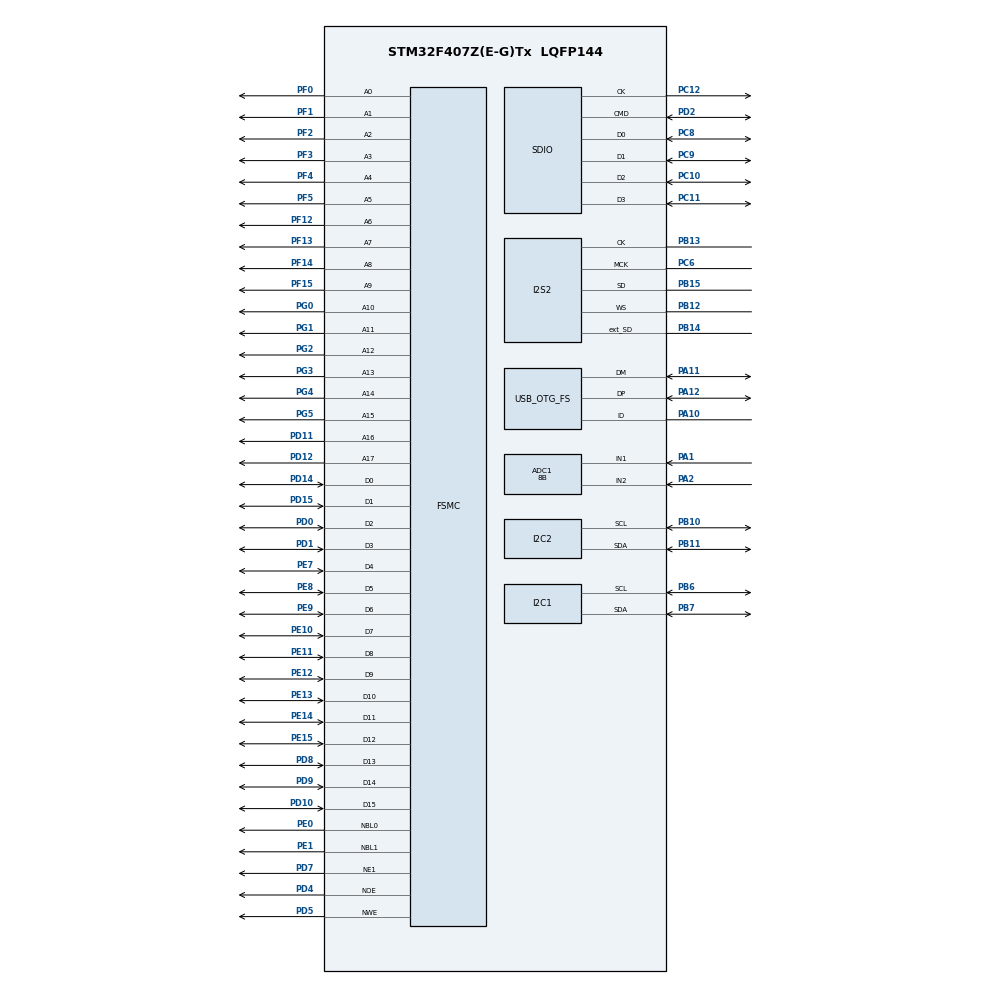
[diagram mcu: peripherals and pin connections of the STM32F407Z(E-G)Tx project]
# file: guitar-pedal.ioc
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ADC1.AutoInjectedConv=DISABLE
ADC1.Channel-0\#ChannelRegularConversion=ADC_CHANNEL_1
ADC1.ClockPrescaler=ADC_CLOCK_SYNC_PCLK_DIV2
ADC1.ContinuousConvMode=DISABLE
ADC1.DMAContinuousRequests=DISABLE
ADC1.DataAlign=ADC_DATAALIGN_RIGHT
ADC1.DiscontinuousConvMode=DISABLE
ADC1.EOCSelection=ADC_EOC_SINGLE_CONV
ADC1.EnableAnalogWatchDog=false
ADC1.ExternalTrigConv=ADC_SOFTWARE_START
ADC1.ExternalTrigConvEdge=ADC_EXTERNALTRIGCONVEDGE_NONE
ADC1.InjNumberOfConversion=0
ADC1.InjectedDiscontinuousConvMode=DISABLE
ADC1.NbrOfConversion=1
ADC1.NbrOfConversionFlag=1
ADC1.Rank-0\#ChannelRegularConversion=1
ADC1.Resolution=ADC_RESOLUTION_8B
ADC1.SamplingTime-0\#ChannelRegularConversion=ADC_SAMPLETIME_3CYCLES
ADC1.ScanConvMode=DISABLE
ADC1.master=1
Dma.I2S2_EXT_RX.1.Direction=DMA_PERIPH_TO_MEMORY
Dma.I2S2_EXT_RX.1.FIFOMode=DMA_FIFOMODE_DISABLE
Dma.I2S2_EXT_RX.1.Instance=DMA1_Stream3
Dma.I2S2_EXT_RX.1.MemDataAlignment=DMA_MDATAALIGN_BYTE
Dma.I2S2_EXT_RX.1.MemInc=DMA_MINC_ENABLE
Dma.I2S2_EXT_RX.1.Mode=DMA_NORMAL
Dma.I2S2_EXT_RX.1.PeriphDataAlignment=DMA_PDATAALIGN_BYTE
Dma.I2S2_EXT_RX.1.PeriphInc=DMA_PINC_DISABLE
Dma.I2S2_EXT_RX.1.Priority=DMA_PRIORITY_LOW
Dma.Request0=SPI2_TX
Dma.Request1=I2S2_EXT_RX
Dma.SPI2_TX.0.Direction=DMA_MEMORY_TO_PERIPH
Dma.SPI2_TX.0.FIFOMode=DMA_FIFOMODE_DISABLE
Dma.SPI2_TX.0.Instance=DMA1_Stream4
Dma.SPI2_TX.0.MemDataAlignment=DMA_MDATAALIGN_BYTE
Dma.SPI2_TX.0.MemInc=DMA_MINC_ENABLE
Dma.SPI2_TX.0.Mode=DMA_NORMAL
Dma.SPI2_TX.0.PeriphDataAlignment=DMA_PDATAALIGN_BYTE
Dma.SPI2_TX.0.PeriphInc=DMA_PINC_DISABLE
Dma.SPI2_TX.0.Priority=DMA_PRIORITY_LOW
FATFS._USE_BUFF_WO_ALIGNMENT=2
FATFS._USE_ERASE=0
FREERTOS.Tasks01=defaultTask,0,128,StartDefaultTask,Default,NULL
FREERTOS.configUSE_ALTERNATIVE_API=0
FSMC.AccessMode1=FSMC_ACCESS_MODE_A
FSMC.AsynchronousWait1=FSMC_ASYNCHRONOUS_WAIT_DISABLE
FSMC.BurstAccessMode1=FSMC_BURST_ACCESS_MODE_DISABLE
FSMC.CLKDivision1=16
FSMC.DataAddressMux1=FSMC_DATA_ADDRESS_MUX_DISABLE
FSMC.DataLatency1=17
FSMC.Extended=FSMC_NORSRAM_EXTENDED_DEVICE
FSMC.NORSRAM_Instance=FSMC_NORSRAM_DEVICE
FSMC.NSCoherentPinout1=MEMORY_PINOUT_OK
FSMC.NSMemoryDataWidth1=FSMC_NORSRAM_MEM_BUS_WIDTH_16
FSMC.PageSize1=FSMC_PAGE_SIZE_NONE
FSMC.WaitSignal1=FSMC_WAIT_SIGNAL_DISABLE
FSMC.WaitSignalActive1=FSMC_WAIT_TIMING_BEFORE_WS
FSMC.WaitSignalPolarity1=FSMC_WAIT_SIGNAL_POLARITY_LOW
FSMC.WrapMode1=FSMC_WRAP_MODE_DISABLE
FSMC.WriteBurst1=FSMC_WRITE_BURST_DISABLE
I2C1.DutyCycle=I2C_DUTYCYCLE_2
I2C1.I2C_Mode=I2C_Standard
I2C2.DutyCycle=I2C_DUTYCYCLE_2
I2C2.I2C_Mode=I2C_Fast
I2S2.AudioFreq=I2S_AUDIOFREQ_48K
I2S2.DataFormat=I2S_DATAFORMAT_24B
I2S2.ErrorAudioFreq=-0.17 %
I2S2.FullDuplexMode=I2S_FULLDUPLEXMODE_ENABLE
I2S2.Instance=SPI$Index
I2S2.MCLKOutput=I2S_MCLKOUTPUT_ENABLE
I2S2.Mode=I2S_MODE_MASTER_TX
I2S2.RealAudioFreq=47.916 KHz
I2S2.Standard=I2S_STANDARD_PHILIPS
I2S2.VirtualMode=I2S_MODE_MASTER
Mcu.Family=STM32F4
Mcu.Name=STM32F407Z(E-G)Tx
Mcu.Package=LQFP144
NVIC.DMA1_Stream3_IRQn=true\:5\:0\:false\:false\:true\:true
NVIC.DMA1_Stream4_IRQn=true\:5\:0\:false\:false\:true\:true
NVIC.PriorityGroup=NVIC_PRIORITYGROUP_4
NVIC.TIM1_UP_TIM10_IRQn=true\:0\:0\:false\:false\:true\:false
NVIC.TimeBase=TIM1_UP_TIM10_IRQn
NVIC.TimeBaseIP=TIM1
PA1.Signal=ADCx_IN1
PA10.Mode=OTG/Dual_Role_Device
PA10.Signal=USB_OTG_FS_ID
PA11.Mode=OTG/Dual_Role_Device
PA11.Signal=USB_OTG_FS_DM
PA12.Mode=OTG/Dual_Role_Device
PA12.Signal=USB_OTG_FS_DP
PA2.Signal=ADCx_IN2
PB10.GPIO_PuPdOD=GPIO_NOPULL
PB10.Mode=I2C
PB10.Signal=I2C2_SCL
PB11.GPIO_PuPdOD=GPIO_NOPULL
PB11.Mode=I2C
PB11.Signal=I2C2_SDA
PB12.Mode=Full_Duplex_Master
PB12.Signal=I2S2_WS
PB13.Mode=Full_Duplex_Master
PB13.Signal=I2S2_CK
PB14.Mode=Full_Duplex_Master
PB14.Signal=I2S2_ext_SD
PB15.Mode=Full_Duplex_Master
PB15.Signal=I2S2_SD
PB6.Mode=I2C
PB6.Signal=I2C1_SCL
PB7.Mode=I2C
PB7.Signal=I2C1_SDA
PC10.Mode=SD_4_bits_Wide_bus
PC10.Signal=SDIO_D2
PC11.Mode=SD_4_bits_Wide_bus
PC11.Signal=SDIO_D3
PC12.Mode=SD_4_bits_Wide_bus
PC12.Signal=SDIO_CK
PC6.Mode=Master_Clock_Activated
PC6.Signal=I2S2_MCK
PC8.Mode=SD_4_bits_Wide_bus
PC8.Signal=SDIO_D0
PC9.Mode=SD_4_bits_Wide_bus
PC9.Signal=SDIO_D1
PD0.Signal=FSMC_D2_DA2
PD1.Signal=FSMC_D3_DA3
PD10.Signal=FSMC_D15_DA15
PD11.Signal=FSMC_A16_CLE
PD12.Signal=FSMC_A17_ALE
PD14.Signal=FSMC_D0_DA0
PD15.Signal=FSMC_D1_DA1
PD2.Mode=SD_4_bits_Wide_bus
PD2.Signal=SDIO_CMD
PD4.Signal=FSMC_NOE
PD5.Signal=FSMC_NWE
PD7.Mode=NorPsramChipSelect1_1
PD7.Signal=FSMC_NE1
PD8.Signal=FSMC_D13_DA13
PD9.Signal=FSMC_D14_DA14
PE0.Signal=FSMC_NBL0
PE1.Signal=FSMC_NBL1
PE10.Signal=FSMC_D7_DA7
PE11.Signal=FSMC_D8_DA8
PE12.Signal=FSMC_D9_DA9
PE13.Signal=FSMC_D10_DA10
PE14.Signal=FSMC_D11_DA11
PE15.Signal=FSMC_D12_DA12
PE7.Signal=FSMC_D4_DA4
PE8.Signal=FSMC_D5_DA5
PE9.Signal=FSMC_D6_DA6
PF0.Signal=FSMC_A0
PF1.Signal=FSMC_A1
PF12.Signal=FSMC_A6
PF13.Signal=FSMC_A7
PF14.Signal=FSMC_A8
PF15.Signal=FSMC_A9
PF2.Signal=FSMC_A2
PF3.Signal=FSMC_A3
PF4.Signal=FSMC_A4
PF5.Signal=FSMC_A5
PG0.Signal=FSMC_A10
PG1.Signal=FSMC_A11
PG2.Signal=FSMC_A12
PG3.Signal=FSMC_A13
PG4.Signal=FSMC_A14
PG5.Signal=FSMC_A15
PH0-OSC_IN.Mode=HSE-External-Oscillator
PH0-OSC_IN.Signal=RCC_OSC_IN
PH1-OSC_OUT.Mode=HSE-External-Oscillator
PH1-OSC_OUT.Signal=RCC_OSC_OUT
ProjectManager.HeapSize=0x200
ProjectManager.StackSize=0x400
ProjectManager.TargetToolchain=SW4STM32
RCC.48MHZClocksFreq_Value=48000000
RCC.AHBFreq_Value=16000000
RCC.APB1Freq_Value=16000000
RCC.APB1TimFreq_Value=16000000
RCC.APB2Freq_Value=16000000
RCC.APB2TimFreq_Value=16000000
RCC.ClockTypeHCLK=RCC_CLOCKTYPE_HCLK
RCC.ClockTypePCLK1=RCC_CLOCKTYPE_PCLK1
RCC.ClockTypePCLK2=RCC_CLOCKTYPE_PCLK2
RCC.ClockTypeSysClk=RCC_CLOCKTYPE_SYSCLK
RCC.CortexFreq_Value=16000000
RCC.EnableExtClockForI2S=false
RCC.EnableHSE=true
RCC.EnableHSERTCDevisor=false
RCC.EnableLSE=false
RCC.EnableLSERTC=false
RCC.ExtClockEnable=false
RCC.HCLKFreq_Value=16000000
RCC.HSEState=RCC_HSE_ON
RCC.HSE_VALUE=16000000
RCC.HSIState=RCC_HSI_ON
RCC.HSI_VALUE=16000000
RCC.I2SEnable=true
RCC.IWDGEnable=false
RCC.LSE_VALUE=32768
RCC.LSIState=RCC_LSI_OFF
RCC.MCO1OutPutEnable=false
RCC.MCO2OutPutEnable=false
RCC.OscillatorTypeHSE=RCC_OSCILLATORTYPE_HSE
RCC.OscillatorTypeHSI=RCC_OSCILLATORTYPE_HSI
RCC.PLLI2SN=184
RCC.PLLI2SR=3
RCC.PLLSource=RCC_PLLSOURCE_HSE
RCC.PLLSourceVirtual=RCC_PLLSOURCE_HSE
RCC.PLLState=RCC_PLL_ON
RCC.RCC_PERIPHCLK_I2SVar=RCC_PERIPHCLK_I2S
RCC.RCC_PERIPHCLK_RTCVar=RCC_PERIPHCLK_RTC
RCC.RNGEnable=false
RCC.RTCEnable=false
RCC.SDIOEnable=true
RCC.SYSCLKFreq_VALUE=16000000
RCC.SYSCLKSource=RCC_SYSCLKSOURCE_HSI
RCC.USBFSEnable=true
RCC.USBHSEnable=false
RCC.VCOOutputFreq_Value=192000000
RCC.VDD_VALUE=3.3
SDIO.BusWide=SDIO_BUS_WIDE_1B
SDIO.ClockBypass=SDIO_CLOCK_BYPASS_DISABLE
SDIO.ClockEdge=SDIO_CLOCK_EDGE_RISING
SDIO.ClockPowerSave=SDIO_CLOCK_POWER_SAVE_DISABLE
SDIO.HardwareFlowControl=SDIO_HARDWARE_FLOW_CONTROL_DISABLE
SDIO.WideMode=SDIO_BUS_WIDE_4B
SH.ADCx_IN1.0=ADC1_IN1,IN1
SH.ADCx_IN2.0=ADC1_IN2,IN2
SH.FSMC_A0.0=FSMC_A0,18b-a1
SH.FSMC_A1.0=FSMC_A1,18b-a1
SH.FSMC_A10.0=FSMC_A10,18b-a1
SH.FSMC_A11.0=FSMC_A11,18b-a1
SH.FSMC_A12.0=FSMC_A12,18b-a1
SH.FSMC_A13.0=FSMC_A13,18b-a1
SH.FSMC_A14.0=FSMC_A14,18b-a1
SH.FSMC_A15.0=FSMC_A15,18b-a1
SH.FSMC_A16_CLE.0=FSMC_A16,18b-a1
SH.FSMC_A17_ALE.0=FSMC_A17,18b-a1
SH.FSMC_A2.0=FSMC_A2,18b-a1
SH.FSMC_A3.0=FSMC_A3,18b-a1
SH.FSMC_A4.0=FSMC_A4,18b-a1
SH.FSMC_A5.0=FSMC_A5,18b-a1
SH.FSMC_A6.0=FSMC_A6,18b-a1
SH.FSMC_A7.0=FSMC_A7,18b-a1
SH.FSMC_A8.0=FSMC_A8,18b-a1
SH.FSMC_A9.0=FSMC_A9,18b-a1
SH.FSMC_D0_DA0.0=FSMC_D0,16b-d1
SH.FSMC_D10_DA10.0=FSMC_D10,16b-d1
SH.FSMC_D11_DA11.0=FSMC_D11,16b-d1
SH.FSMC_D12_DA12.0=FSMC_D12,16b-d1
SH.FSMC_D13_DA13.0=FSMC_D13,16b-d1
SH.FSMC_D14_DA14.0=FSMC_D14,16b-d1
SH.FSMC_D15_DA15.0=FSMC_D15,16b-d1
SH.FSMC_D1_DA1.0=FSMC_D1,16b-d1
SH.FSMC_D2_DA2.0=FSMC_D2,16b-d1
SH.FSMC_D3_DA3.0=FSMC_D3,16b-d1
SH.FSMC_D4_DA4.0=FSMC_D4,16b-d1
SH.FSMC_D5_DA5.0=FSMC_D5,16b-d1
SH.FSMC_D6_DA6.0=FSMC_D6,16b-d1
SH.FSMC_D7_DA7.0=FSMC_D7,16b-d1
SH.FSMC_D8_DA8.0=FSMC_D8,16b-d1
SH.FSMC_D9_DA9.0=FSMC_D9,16b-d1
SH.FSMC_NBL0.0=FSMC_NBL0,2ByteEnable1
SH.FSMC_NBL1.0=FSMC_NBL1,2ByteEnable1
SH.FSMC_NOE.0=FSMC_NOE,Sram1
SH.FSMC_NWE.0=FSMC_NWE,Sram1
VP_FATFS_VS_SDIO.Mode=SDIO
VP_FREERTOS_VS_ENABLE.Mode=Enabled
VP_SYS_VS_tim1.Mode=TIM1
board=guitar-pedal

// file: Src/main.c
/**
  ******************************************************************************
  * File Name          : main.c
  * Description        : Main program body
  ******************************************************************************
  *
  * Copyright (c) 2017 STMicroelectronics International N.V.
  * All rights reserved.
  *
  * Redistribution and use in source and binary forms, with or without
  * modification, are permitted, provided that the following conditions are met:
  *
  * 1. Redistribution of source code must retain the above copyright notice,
  *    this list of conditions and the following disclaimer.
  * 2. Redistributions in binary form must reproduce the above copyright notice,
  *    this list of conditions and the following disclaimer in the documentation
  *    and/or other materials provided with the distribution.
  * 3. Neither the name of STMicroelectronics nor the names of other
  *    contributors to this software may be used to endorse or promote products
  *    derived from this software without specific written permission.
  * 4. This software, including modifications and/or derivative works of this
  *    software, must execute solely and exclusively on microcontroller or
  *    microprocessor devices manufactured by or for STMicroelectronics.
  * 5. Redistribution and use of this software other than as permitted under
  *    this license is void and will automatically terminate your rights under
  *    this license.
  *
  * THIS SOFTWARE IS PROVIDED BY STMICROELECTRONICS AND CONTRIBUTORS "AS IS"
  * AND ANY EXPRESS, IMPLIED OR STATUTORY WARRANTIES, INCLUDING, BUT NOT
  * LIMITED TO, THE IMPLIED WARRANTIES OF MERCHANTABILITY, FITNESS FOR A
  * PARTICULAR PURPOSE AND NON-INFRINGEMENT OF THIRD PARTY INTELLECTUAL PROPERTY
  * RIGHTS ARE DISCLAIMED TO THE FULLEST EXTENT PERMITTED BY LAW. IN NO EVENT
  * SHALL STMICROELECTRONICS OR CONTRIBUTORS BE LIABLE FOR ANY DIRECT, INDIRECT,
  * INCIDENTAL, SPECIAL, EXEMPLARY, OR CONSEQUENTIAL DAMAGES (INCLUDING, BUT NOT
  * LIMITED TO, PROCUREMENT OF SUBSTITUTE GOODS OR SERVICES; LOSS OF USE, DATA,
  * OR PROFITS; OR BUSINESS INTERRUPTION) HOWEVER CAUSED AND ON ANY THEORY OF
  * LIABILITY, WHETHER IN CONTRACT, STRICT LIABILITY, OR TORT (INCLUDING
  * NEGLIGENCE OR OTHERWISE) ARISING IN ANY WAY OUT OF THE USE OF THIS SOFTWARE,
  * EVEN IF ADVISED OF THE POSSIBILITY OF SUCH DAMAGE.
  *
  ******************************************************************************
  */
#include "main.h"
#include "stm32f4xx_hal.h"
#include "cmsis_os.h"
#include "adc.h"
#include "dma.h"
#include "fatfs.h"
#include "i2c.h"
#include "i2s.h"
#include "sdio.h"
#include "usb_otg.h"
#include "gpio.h"
#include "fsmc.h"

/* USER CODE BEGIN PV */
/* Private variables ---------------------------------------------------------*/

/* USER CODE END PV */

void SystemClock_Config(void);
void Error_Handler(void);
void MX_FREERTOS_Init(void);

/* USER CODE BEGIN PFP */
/* Private function prototypes -----------------------------------------------*/

/* USER CODE END PFP */

int main(void)
 {

  /* MCU Configuration----------------------------------------------------------*/

  /* Reset of all peripherals, Initializes the Flash interface and the Systick. */
  HAL_Init();

  /* Configure the system clock */
  SystemClock_Config();

  /* Initialize all configured peripherals */
  MX_GPIO_Init();
  MX_DMA_Init();
  MX_I2S2_Init();
  MX_FSMC_Init();
  MX_I2C1_Init();
  MX_USB_OTG_FS_USB_Init();
  MX_SDIO_SD_Init();
  MX_ADC1_Init();
  MX_I2C2_Init();

  /* Call init function for freertos objects (in freertos.c) */
  MX_FREERTOS_Init();

  /* Start scheduler */
  osKernelStart();

  /* We should never get here as control is now taken by the scheduler */

}

/** System Clock Configuration
*/
void SystemClock_Config(void)
{

  RCC_OscInitTypeDef RCC_OscInitStruct;
  RCC_ClkInitTypeDef RCC_ClkInitStruct;
  RCC_PeriphCLKInitTypeDef PeriphClkInitStruct;

    /**Configure the main internal regulator output voltage
    */
  __HAL_RCC_PWR_CLK_ENABLE();

  __HAL_PWR_VOLTAGESCALING_CONFIG(PWR_REGULATOR_VOLTAGE_SCALE1);

    /**Initializes the CPU, AHB and APB busses clocks
    */
  RCC_OscInitStruct.OscillatorType = RCC_OSCILLATORTYPE_HSE;
  RCC_OscInitStruct.HSEState = RCC_HSE_ON;
  RCC_OscInitStruct.PLL.PLLState = RCC_PLL_ON;
  RCC_OscInitStruct.PLL.PLLSource = RCC_PLLSOURCE_HSE;
  RCC_OscInitStruct.PLL.PLLM = 8;
  RCC_OscInitStruct.PLL.PLLN = 168;
  RCC_OscInitStruct.PLL.PLLP = RCC_PLLP_DIV2;
  RCC_OscInitStruct.PLL.PLLQ = 4;
  if (HAL_RCC_OscConfig(&RCC_OscInitStruct) != HAL_OK)
  {
      Error_Handler();
  }

    /**Initializes the CPU, AHB and APB busses clocks
    */
  RCC_ClkInitStruct.ClockType = RCC_CLOCKTYPE_HCLK|RCC_CLOCKTYPE_SYSCLK
                              |RCC_CLOCKTYPE_PCLK1|RCC_CLOCKTYPE_PCLK2;
  RCC_ClkInitStruct.SYSCLKSource = RCC_SYSCLKSOURCE_PLLCLK;
  RCC_ClkInitStruct.AHBCLKDivider = RCC_SYSCLK_DIV1;
  RCC_ClkInitStruct.APB1CLKDivider = RCC_HCLK_DIV4;
  RCC_ClkInitStruct.APB2CLKDivider = RCC_HCLK_DIV2;

  if (HAL_RCC_ClockConfig(&RCC_ClkInitStruct, FLASH_LATENCY_5) != HAL_OK)
  {
      Error_Handler();
  }

  PeriphClkInitStruct.PeriphClockSelection = RCC_PERIPHCLK_I2S;
  PeriphClkInitStruct.PLLI2S.PLLI2SN = 111;
  PeriphClkInitStruct.PLLI2S.PLLI2SR = 2;
  if (HAL_RCCEx_PeriphCLKConfig(&PeriphClkInitStruct) != HAL_OK)
  {
    Error_Handler();
  }

    /**Configure the Systick interrupt time
    */
  HAL_SYSTICK_Config(HAL_RCC_GetHCLKFreq()/1000);

    /**Configure the Systick
    */
  HAL_SYSTICK_CLKSourceConfig(SYSTICK_CLKSOURCE_HCLK);

  /* SysTick_IRQn interrupt configuration */
  HAL_NVIC_SetPriority(SysTick_IRQn, 0, 0);
}

void HAL_TIM_PeriodElapsedCallback(TIM_HandleTypeDef *htim)
{
  if (htim->Instance == TIM1) {
    HAL_IncTick();
  }
}

void Error_Handler(void)
{
  while(1)
  {
  }
}

/************************ (C) COPYRIGHT STMicroelectronics *****END OF FILE****/

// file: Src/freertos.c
/**
  ******************************************************************************
  * File Name          : freertos.c
  * Description        : Code for freertos applications
  ******************************************************************************
  *
  * Copyright (c) 2017 STMicroelectronics International N.V.
  * All rights reserved.
  *
  * Redistribution and use in source and binary forms, with or without
  * modification, are permitted, provided that the following conditions are met:
  *
  * 1. Redistribution of source code must retain the above copyright notice,
  *    this list of conditions and the following disclaimer.
  * 2. Redistributions in binary form must reproduce the above copyright notice,
  *    this list of conditions and the following disclaimer in the documentation
  *    and/or other materials provided with the distribution.
  * 3. Neither the name of STMicroelectronics nor the names of other
  *    contributors to this software may be used to endorse or promote products
  *    derived from this software without specific written permission.
  * 4. This software, including modifications and/or derivative works of this
  *    software, must execute solely and exclusively on microcontroller or
  *    microprocessor devices manufactured by or for STMicroelectronics.
  * 5. Redistribution and use of this software other than as permitted under
  *    this license is void and will automatically terminate your rights under
  *    this license.
  *
  * THIS SOFTWARE IS PROVIDED BY STMICROELECTRONICS AND CONTRIBUTORS "AS IS"
  * AND ANY EXPRESS, IMPLIED OR STATUTORY WARRANTIES, INCLUDING, BUT NOT
  * LIMITED TO, THE IMPLIED WARRANTIES OF MERCHANTABILITY, FITNESS FOR A
  * PARTICULAR PURPOSE AND NON-INFRINGEMENT OF THIRD PARTY INTELLECTUAL PROPERTY
  * RIGHTS ARE DISCLAIMED TO THE FULLEST EXTENT PERMITTED BY LAW. IN NO EVENT
  * SHALL STMICROELECTRONICS OR CONTRIBUTORS BE LIABLE FOR ANY DIRECT, INDIRECT,
  * INCIDENTAL, SPECIAL, EXEMPLARY, OR CONSEQUENTIAL DAMAGES (INCLUDING, BUT NOT
  * LIMITED TO, PROCUREMENT OF SUBSTITUTE GOODS OR SERVICES; LOSS OF USE, DATA,
  * OR PROFITS; OR BUSINESS INTERRUPTION) HOWEVER CAUSED AND ON ANY THEORY OF
  * LIABILITY, WHETHER IN CONTRACT, STRICT LIABILITY, OR TORT (INCLUDING
  * NEGLIGENCE OR OTHERWISE) ARISING IN ANY WAY OUT OF THE USE OF THIS SOFTWARE,
  * EVEN IF ADVISED OF THE POSSIBILITY OF SUCH DAMAGE.
  *
  ******************************************************************************
  */

#include <string.h>
#include <math.h>
#include "FreeRTOS.h"
#include "task.h"
#include "cmsis_os.h"
#include "codec.h"
#include "audio_effects.h"
#include "stm32f4xx_it.h"
#include "stm32f4xx_hal_i2s_ex.h"
#include "codec.h"

osThreadId defaultTaskHandle;
osThreadId codecTaskHandle;

void StartDefaultTask(void const * argument);
void CodecTask(void const * argument);

extern void MX_FATFS_Init(void);
void MX_FREERTOS_Init(void); /* (MISRA C 2004 rule 8.1) */

/* Hook prototypes */

/* Init FreeRTOS */

void MX_FREERTOS_Init(void) {

  /* Create the thread(s) */
  /* definition and creation of defaultTask */
  osThreadDef(defaultTask, StartDefaultTask, osPriorityNormal, 0, 128);
  defaultTaskHandle = osThreadCreate(osThread(defaultTask), NULL);

  /* USER CODE BEGIN RTOS_THREADS */
  /* add threads, ... */
  osThreadDef(codecTask, CodecTask, osPriorityRealtime, 0, 128);
  codecTaskHandle = osThreadCreate(osThread(codecTask), NULL);
  /* USER CODE END RTOS_THREADS */

}

/* StartDefaultTask function */
void StartDefaultTask(void const * argument)
{
  /* init code for FATFS */
  MX_FATFS_Init();

  /* USER CODE BEGIN StartDefaultTask */

  /* Infinite loop */

  for(;;)
  {
    taskYIELD();
  }
  /* USER CODE END StartDefaultTask */
}

/* USER CODE BEGIN Application */
void CodecTask(void const * argument)
{
  //uint32_t formattedData[66] = {0};
  memset(codecTxBuffer, 0x00000000, BUFFER_SIZE * sizeof(uint16_t));
  memset(codecRxBuffer, 0x00000000, BUFFER_SIZE * sizeof(uint16_t));
 // memset(codecTxBuffer_Long, 0x00000000, BUFFER_SIZE * sizeof(uint16_t));

 // memset(EMPTY, 0x0000, BUFFER_SIZE * sizeof(int32_t));
  volatile int16_t i,k,j= 0;
  volatile int16_t in,out= 0;

  //volatile uint32_t INPUT[BUFFER_SIZE/2] =  {1638556, 1573021, 1376411, 1507484, 1638556, 1638553, 1966242, 1966242, 1835167, 1310874, 1376410, 1376408, 1441945, 1441945, 1507482, 1441946};
  //volatile int16_t INPUT2[BUFFER_SIZE] =  {0, 65535, 0, 65535, 0, 65535, 0,65535};
  //volatile int32_t INPUT[BUFFER_SIZE/2] =  {0, 100, 0, 100, 0, 100, 0, 100, 0, 100, 0, 100, 0, 100, 0, 100};

  CODEC_Init();
  // Start codec transfer
  while(hdma_spi2_tx.State != HAL_DMA_STATE_READY);
  CODEC_sendReceive((uint16_t*)codecTxBuffer,(uint16_t*)codecRxBuffer);
  //codec_EnableBypass(1);
  //I2SDMARxCompleted = 1;

  for(;;)
  {
    if(((j*BUFFER_SIZE)%MAX_BUFFER) ==0){
        j =0;
    }

    k = (j*BUFFER_SIZE)%MAX_BUFFER;
    // Wait to receive data
    if( I2SDMARxCompleted)
    {
      // Update flags
      I2SDMARxCompleted = 0;
      I2SDMATxCompleted = 0;

     // Apply audio effect

      for(i = 0; i<(BUFFER_SIZE/2); i++){
          in = codecRxBuffer[i];
          out = REVERB(DelayBuffer, OutputBuffer, in,k,i);
          //Fill buffers
          DelayBuffer[k+i] = in;
          codecTxBuffer[i] = out;
      }
          //codecTxBuffer_Long = Data_Full;
          CODEC_sendReceive((uint16_t*)codecTxBuffer,(uint16_t*)codecRxBuffer);
          j++;
    }
//      for(i = 0; i<(BUFFER_SIZE/2); i++){
//      out = ((codecRxBuffer[2*i]<<8) & 0xff00) | (codecRxBuffer[2*i+1] & 0x00ff);
//      EMPTY[i*2+1] = out;
//      }

//     while(hdma_spi2_tx.State != HAL_DMA_STATE_READY);
//      codecTxBuffer[0] = codecRxBuffer[0]; //R

//      codecTxBuffer[1] = 0;//1000;
//      codecTxBuffer[2] = 0; //L
//      codecTxBuffer[3] = 0;
//      codecTxBuffer[4] = 0; //R
//      codecTxBuffer[5] = 0;//1000;
//      codecTxBuffer[6] = 0; //L
//      codecTxBuffer[7] = 0;
      //while(hdma_spi2_tx.State != HAL_DMA_STATE_READY);

    }

      // Re-package audio data to 24-bit packets
      //memcpy(codecTxBuffer, codecRxBuffer, sizeof(codecRxBuffer));

     // Transfer to codec

}

/* USER CODE END Application */

/************************ (C) COPYRIGHT STMicroelectronics *****END OF FILE****/
